VERSION 5.8 ;
BUSBITCHARS "[]" ;
DIVIDERCHAR "/" ;

SITE  CoreSite2
    CLASS       CORE ;
    SYMMETRY    Y ;
    SIZE        0.48 BY 7.56 ;
END  CoreSite2

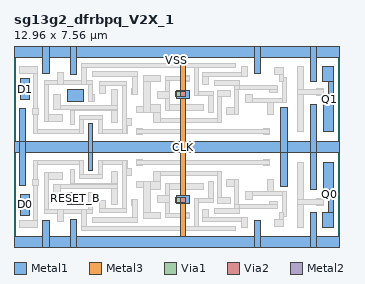
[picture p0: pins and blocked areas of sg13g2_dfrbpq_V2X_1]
MACRO sg13g2_dfrbpq_V2X_1
  CLASS CORE ;
  ORIGIN 0 0 ;
  FOREIGN sg13g2_dfrbpq_V2X_1 0 0 ;
  SIZE 12.960 BY 7.560 ;
  SYMMETRY X Y ;
  SITE CoreSite2 ;
  PIN D0
    DIRECTION INPUT ;
    USE SIGNAL ;
    ANTENNAMODEL OXIDE1 ;
    ANTENNAGATEAREA 0.1092 LAYER Metal1 ;
    PORT
      LAYER Metal1 ;
        RECT 0.255 1.070 0.600 1.890 ;
    END
  END D0
  PIN Q0
    DIRECTION OUTPUT ;
    USE SIGNAL ;
    ANTENNADIFFAREA 0.6324 LAYER Metal1 ;
    PORT
      LAYER Metal1 ;
        RECT 12.275 0.590 12.710 1.190 ;
        RECT 12.500 0.590 12.710 3.155 ;
        RECT 12.295 2.095 12.710 3.155 ;
    END
  END Q0
  PIN D1
    DIRECTION INPUT ;
    USE SIGNAL ;
    ANTENNAMODEL OXIDE1 ;
    ANTENNAGATEAREA 0.1092 LAYER Metal1 ;
    PORT
      LAYER Metal1 ;
        RECT 0.255 5.670 0.600 6.490 ;
    END
  END D1
  PIN Q1
    DIRECTION OUTPUT ;
    USE SIGNAL ;
    ANTENNADIFFAREA 0.6324 LAYER Metal1 ;
    PORT
      LAYER Metal1 ;
        RECT 12.295 4.405 12.710 5.465 ;
        RECT 12.500 4.405 12.710 6.970 ;
        RECT 12.275 6.370 12.710 6.970 ;
    END
  END Q1
  PIN VDD
    DIRECTION INOUT ;
    USE POWER ;
    SHAPE ABUTMENT ;
    NETEXPR "VDD VDD!" ;
    PORT
      LAYER Metal1 ;
        RECT 11.785 2.100 12.045 4.000 ;
        RECT 10.610 2.225 10.875 4.000 ;
        RECT 0.215 2.240 0.475 4.000 ;
        RECT 2.945 2.860 3.115 4.000 ;
        RECT 0.000 3.560 12.960 4.000 ;
        RECT 2.945 3.560 3.115 4.700 ;
        RECT 0.215 3.560 0.475 5.320 ;
        RECT 10.610 3.560 10.875 5.335 ;
        RECT 11.785 3.560 12.045 5.460 ;
    END
  END VDD
  PIN VSS
    DIRECTION INOUT ;
    USE GROUND ;
    SHAPE ABUTMENT ;
    NETEXPR "VSS VSS!" ;
    PORT
      LAYER Metal1 ;
        RECT 0.000 -0.220 12.960 0.220 ;
        RECT 9.560 -0.220 9.820 0.850 ;
        RECT 1.140 -0.220 1.410 0.850 ;
        RECT 2.235 -0.220 2.495 0.915 ;
        RECT 11.785 -0.220 12.045 1.190 ;
    END
    PORT
      LAYER Metal1 ;
        RECT 11.785 6.370 12.045 7.780 ;
        RECT 2.235 6.645 2.495 7.780 ;
        RECT 9.560 6.710 9.820 7.780 ;
        RECT 1.140 6.710 1.410 7.780 ;
        RECT 0.000 7.340 12.960 7.780 ;
    END
  END VSS
  PIN CLK
    DIRECTION INPUT ;
    USE SIGNAL ;
    ANTENNAMODEL OXIDE1 ;
    ANTENNAGATEAREA 0.2418 LAYER Metal1 ;
    PORT
      LAYER Metal1 ;
        RECT 6.450 1.520 6.990 1.840 ;
        RECT 6.450 5.720 6.990 6.040 ;
      LAYER Metal3 ;
        RECT 6.620 0.200 6.820 7.360 ;
      LAYER Via1 ;
        RECT 6.450 1.585 6.640 1.775 ;
      LAYER Via2 ;
        RECT 6.620 1.585 6.810 1.775 ;
      LAYER Metal2 ;
        RECT 6.445 1.580 6.815 1.780 ;
      LAYER Via1 ;
        RECT 6.450 5.785 6.640 5.975 ;
      LAYER Via2 ;
        RECT 6.620 5.785 6.810 5.975 ;
      LAYER Metal2 ;
        RECT 6.445 5.780 6.815 5.980 ;
    END
  END CLK
  PIN RESET_B
    DIRECTION INPUT ;
    USE SIGNAL ;
    ANTENNAPARTIALMETALAREA 0.8998 LAYER Metal1 ;
    ANTENNAMODEL OXIDE1 ;
    ANTENNAGATEAREA 0.3276 LAYER Metal1 ;
    ANTENNAMAXAREACAR 2.746642 LAYER Metal1 ;
    PORT
      LAYER Metal1 ;
        RECT 2.145 1.510 2.750 1.965 ;
    END
    PORT
      LAYER Metal1 ;
        RECT 2.145 5.595 2.750 6.050 ;
    END
  END RESET_B
  OBS
    LAYER Metal1 ;
      RECT 11.275 0.590 11.535 3.155 ;
      RECT 12.020 1.445 12.320 1.745 ;
      RECT 11.275 1.485 12.320 1.710 ;
      RECT 10.070 1.860 10.330 2.495 ;
      RECT 9.220 1.860 10.835 2.020 ;
      RECT 10.675 1.030 10.835 2.020 ;
      RECT 9.220 1.690 9.480 2.020 ;
      RECT 10.570 0.625 10.730 1.190 ;
      RECT 10.380 0.625 10.730 0.885 ;
      RECT 8.475 2.225 8.950 2.485 ;
      RECT 8.790 1.145 8.950 2.485 ;
      RECT 10.165 1.350 10.470 1.625 ;
      RECT 8.790 1.350 10.470 1.510 ;
      RECT 8.790 1.145 8.970 1.510 ;
      RECT 7.960 1.145 8.970 1.315 ;
      RECT 9.910 3.025 10.160 3.285 ;
      RECT 4.855 3.025 5.115 3.285 ;
      RECT 4.855 3.075 10.160 3.235 ;
      RECT 7.510 0.805 7.725 1.310 ;
      RECT 7.510 0.805 9.310 0.965 ;
      RECT 9.050 0.590 9.310 0.965 ;
      RECT 1.200 2.500 1.940 2.760 ;
      RECT 1.200 1.150 1.360 2.760 ;
      RECT 7.745 1.555 7.935 2.425 ;
      RECT 2.950 1.705 3.210 1.965 ;
      RECT 7.170 1.555 7.935 1.725 ;
      RECT 2.950 1.150 3.110 1.965 ;
      RECT 7.170 0.440 7.330 1.725 ;
      RECT 1.200 1.150 3.110 1.310 ;
      RECT 2.705 0.440 2.875 1.310 ;
      RECT 1.720 0.815 1.980 1.310 ;
      RECT 8.540 0.440 8.800 0.625 ;
      RECT 2.705 0.440 8.800 0.605 ;
      RECT 5.550 2.630 8.275 2.800 ;
      RECT 8.115 1.525 8.275 2.800 ;
      RECT 5.550 2.070 5.810 2.800 ;
      RECT 4.855 2.160 5.810 2.420 ;
      RECT 5.145 2.070 5.810 2.420 ;
      RECT 5.145 0.920 5.420 2.420 ;
      RECT 8.115 1.525 8.600 1.785 ;
      RECT 5.145 0.920 5.815 1.180 ;
      RECT 6.020 2.070 7.525 2.330 ;
      RECT 6.020 0.980 6.180 2.330 ;
      RECT 5.725 1.575 6.180 1.835 ;
      RECT 6.755 0.920 6.990 1.180 ;
      RECT 6.020 0.980 6.990 1.140 ;
      RECT 4.660 1.440 4.905 1.700 ;
      RECT 4.725 0.785 4.905 1.700 ;
      RECT 3.120 0.785 4.905 0.960 ;
      RECT 3.365 3.080 4.505 3.240 ;
      RECT 4.320 2.655 4.505 3.240 ;
      RECT 0.785 3.080 2.765 3.240 ;
      RECT 2.605 2.520 2.765 3.240 ;
      RECT 3.365 2.520 3.535 3.240 ;
      RECT 0.785 0.590 0.950 3.240 ;
      RECT 4.320 2.655 4.665 2.915 ;
      RECT 2.605 2.520 3.535 2.680 ;
      RECT 4.320 1.160 4.480 3.240 ;
      RECT 0.720 2.240 0.980 2.500 ;
      RECT 3.385 1.160 3.645 1.640 ;
      RECT 3.385 1.160 4.480 1.320 ;
      RECT 0.210 0.590 0.950 0.850 ;
      RECT 2.245 2.145 2.425 2.900 ;
      RECT 3.895 1.500 4.115 2.805 ;
      RECT 2.245 2.145 4.115 2.315 ;
      RECT 1.585 2.145 4.115 2.305 ;
      RECT 1.585 1.705 1.845 2.305 ;
      RECT 11.275 4.405 11.535 6.970 ;
      RECT 12.020 5.815 12.320 6.115 ;
      RECT 11.275 5.850 12.320 6.075 ;
      RECT 10.070 5.065 10.330 5.700 ;
      RECT 9.220 5.540 10.835 5.700 ;
      RECT 10.675 5.540 10.835 6.530 ;
      RECT 9.220 5.540 9.480 5.870 ;
      RECT 10.570 6.370 10.730 6.935 ;
      RECT 10.380 6.675 10.730 6.935 ;
      RECT 8.475 5.075 8.950 5.335 ;
      RECT 8.790 5.075 8.950 6.415 ;
      RECT 10.165 5.935 10.470 6.210 ;
      RECT 8.790 6.050 10.470 6.210 ;
      RECT 8.790 6.050 8.970 6.415 ;
      RECT 7.960 6.245 8.970 6.415 ;
      RECT 9.910 4.275 10.160 4.535 ;
      RECT 4.855 4.275 5.115 4.535 ;
      RECT 4.855 4.325 10.160 4.485 ;
      RECT 7.510 6.250 7.725 6.755 ;
      RECT 7.510 6.595 9.310 6.755 ;
      RECT 9.050 6.595 9.310 6.970 ;
      RECT 1.200 4.800 1.940 5.060 ;
      RECT 1.200 4.800 1.360 6.410 ;
      RECT 7.745 5.135 7.935 6.005 ;
      RECT 2.950 5.595 3.210 5.855 ;
      RECT 7.170 5.835 7.935 6.005 ;
      RECT 2.950 5.595 3.110 6.410 ;
      RECT 7.170 5.835 7.330 7.120 ;
      RECT 1.200 6.250 3.110 6.410 ;
      RECT 2.705 6.250 2.875 7.120 ;
      RECT 1.720 6.250 1.980 6.745 ;
      RECT 8.540 6.935 8.800 7.120 ;
      RECT 2.705 6.955 8.800 7.120 ;
      RECT 5.550 4.760 8.275 4.930 ;
      RECT 8.115 4.760 8.275 6.035 ;
      RECT 5.550 4.760 5.810 5.490 ;
      RECT 4.855 5.140 5.810 5.400 ;
      RECT 5.145 5.140 5.810 5.490 ;
      RECT 5.145 5.140 5.420 6.640 ;
      RECT 8.115 5.775 8.600 6.035 ;
      RECT 5.145 6.380 5.815 6.640 ;
      RECT 6.020 5.230 7.525 5.490 ;
      RECT 6.020 5.230 6.180 6.580 ;
      RECT 5.725 5.725 6.180 5.985 ;
      RECT 6.755 6.380 6.990 6.640 ;
      RECT 6.020 6.420 6.990 6.580 ;
      RECT 4.660 5.860 4.905 6.120 ;
      RECT 4.725 5.860 4.905 6.775 ;
      RECT 3.120 6.600 4.905 6.775 ;
      RECT 3.365 4.320 4.505 4.480 ;
      RECT 4.320 4.320 4.505 4.905 ;
      RECT 0.785 4.320 2.765 4.480 ;
      RECT 2.605 4.320 2.765 5.040 ;
      RECT 3.365 4.320 3.535 5.040 ;
      RECT 0.785 4.320 0.950 6.970 ;
      RECT 4.320 4.645 4.665 4.905 ;
      RECT 2.605 4.880 3.535 5.040 ;
      RECT 4.320 4.320 4.480 6.400 ;
      RECT 0.720 5.060 0.980 5.320 ;
      RECT 3.385 5.920 3.645 6.400 ;
      RECT 3.385 6.240 4.480 6.400 ;
      RECT 0.210 6.710 0.950 6.970 ;
      RECT 2.245 4.660 2.425 5.415 ;
      RECT 3.895 4.755 4.115 6.060 ;
      RECT 2.245 5.245 4.115 5.415 ;
      RECT 1.585 5.255 4.115 5.415 ;
      RECT 1.585 5.255 1.845 5.855 ;
  END
END sg13g2_dfrbpq_V2X_1

END LIBRARY
